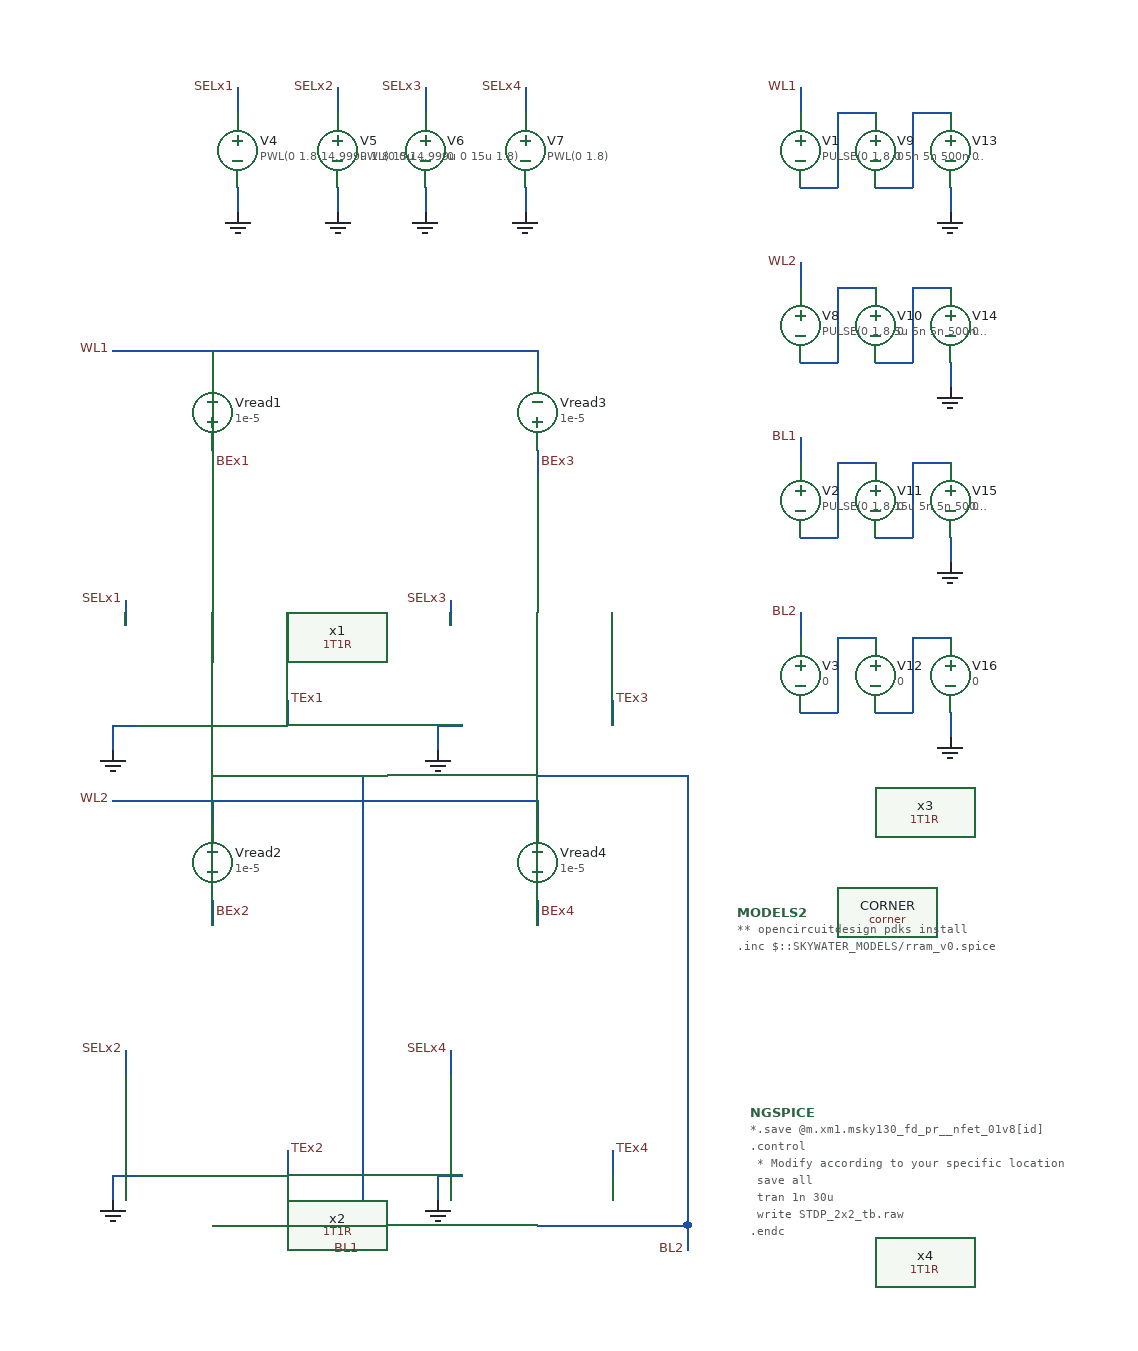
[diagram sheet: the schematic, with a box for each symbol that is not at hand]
v {xschem version=3.4.5 file_version=1.2
}
G {}
K {}
V {}
S {}
E {}
B 2 -930 -1240 -130 -840 {flags=graph
y1=-150000
y2=2.9e+06
ypos1=0
ypos2=2
divy=5
subdivy=1
unity=1
x1=0
x2=3e-05
divx=5
subdivx=1
xlabmag=1.0
ylabmag=1.0
node="\\"M[Ohms];\\"
\\"M1;TEx1 BEx1 - i(Vread1) /\\"
\\"M2;TEx2 BEx2 - i(Vread2) /\\"
\\"M3;TEx3 BEx3 - i(Vread3) /\\"
\\"M4;TEx4 BEx4 - i(Vread4) /\\""
color="4 8 6 7 10"
dataset=-1
unitx=1
logx=0
logy=0
}
B 2 -130 -1240 670 -840 {flags=graph
y1=0
y2=3
ypos1=0
ypos2=2
divy=5
subdivy=1
unity=1
x1=0
x2=3e-05
divx=5
subdivx=1
xlabmag=1.0
ylabmag=1.0
node="\\"SELx1[V];SELx1\\"
\\"SELx2[V];SELx2\\"
\\"SELx3[V];SELx3\\"
\\"SELx4[V];SELx4\\""
color="8 6 7 10"
dataset=-1
unitx=1
logx=0
logy=0
}
B 2 -930 -840 -130 -440 {flags=graph
y1=-5.3e-05
y2=6.6e-05
ypos1=0
ypos2=2
divy=5
subdivy=1
unity=1
x1=0
x2=3e-05
divx=5
subdivx=1
xlabmag=1.0
ylabmag=1.0


dataset=-1
unitx=1
logx=0
logy=0
color="4 8 6 7 10"
node="\\"Current (A);\\"
\\"i1;0 i(Vread1) -\\"
\\"i2;0 i(Vread2) -\\"
\\"i3;0 i(Vread3) -\\"
\\"i4;0 i(Vread4) -\\""}
B 2 -130 -840 670 -440 {flags=graph
y1=0
y2=1.8
ypos1=0
ypos2=2
divy=5
subdivy=1
unity=1
x1=0
x2=3e-05
divx=5
subdivx=1
xlabmag=1.0
ylabmag=1.0


dataset=-1
unitx=1
logx=0
logy=0
color="4 8 6 7 10"
node="\\"Voltage (V);\\"
\\"WL1;WL1\\"
\\"WL2;WL2\\"
\\"BL1;BL1\\"
\\"BL2;BL2\\""}
N -1640 -690 -1520 -690 {
lab=BL1}
N -1640 -330 -1520 -330 {
lab=BL1}
N -1380 -330 -1260 -330 {
lab=BL2}
N -1380 -690 -1260 -690 {
lab=BL2}
N -1460 -730 -1460 -710 {
lab=GND}
N -1460 -730 -1440 -730 {
lab=GND}
N -1720 -730 -1720 -710 {
lab=GND}
N -1720 -730 -1700 -730 {
lab=GND}
N -1720 -370 -1720 -350 {
lab=GND}
N -1720 -370 -1700 -370 {
lab=GND}
N -1460 -370 -1460 -350 {
lab=GND}
N -1460 -370 -1440 -370 {
lab=GND}
N -1710 -830 -1710 -810 {
lab=SELx1}
N -1450 -830 -1450 -810 {
lab=SELx3}
N -1450 -470 -1450 -450 {
lab=SELx4}
N -1710 -470 -1710 -450 {
lab=SELx2}
N -1580 -390 -1580 -370 {
lab=TEx2}
N -1580 -750 -1580 -730 {
lab=TEx1}
N -1320 -750 -1320 -730 {
lab=TEx3}
N -1320 -390 -1320 -370 {
lab=TEx4}
N -1170 -1240 -1170 -1220 {
lab=WL1}
N -1170 -960 -1170 -940 {
lab=BL1}
N -1170 -820 -1170 -800 {
lab=BL2}
N -1520 -330 -1520 -310 {
lab=BL1}
N -1260 -330 -1260 -310 {
lab=BL2}
N -1620 -1160 -1620 -1140 {
lab=GND}
N -1620 -1240 -1620 -1220 {
lab=SELx1}
N -1540 -1160 -1540 -1140 {
lab=GND}
N -1540 -1240 -1540 -1220 {
lab=SELx2}
N -1470 -1160 -1470 -1140 {
lab=GND}
N -1470 -1240 -1470 -1220 {
lab=SELx3}
N -1390 -1160 -1390 -1140 {
lab=GND}
N -1390 -1240 -1390 -1220 {
lab=SELx4}
N -1380 -950 -1380 -930 {
lab=BEx3}
N -1640 -950 -1640 -930 {
lab=BEx1}
N -1720 -1030 -1380 -1030 {
lab=WL1}
N -1380 -1030 -1380 -1010 {
lab=WL1}
N -1640 -1030 -1640 -1010 {
lab=WL1}
N -1640 -590 -1640 -570 {
lab=BEx2}
N -1380 -590 -1380 -570 {
lab=BEx4}
N -1380 -670 -1380 -650 {
lab=WL2}
N -1720 -670 -1380 -670 {
lab=WL2}
N -1640 -670 -1640 -650 {
lab=WL2}
N -1520 -690 -1520 -330 {
lab=BL1}
N -1260 -690 -1260 -330 {
lab=BL2}
N -1170 -1100 -1170 -1080 {
lab=WL2}
N -1050 -1160 -1050 -1140 {
lab=GND}
N -1050 -1020 -1050 -1000 {
lab=GND}
N -1050 -880 -1050 -860 {
lab=GND}
N -1050 -740 -1050 -720 {
lab=GND}
N -1170 -740 -1140 -740 {
lab=#net1}
N -1140 -800 -1140 -740 {
lab=#net1}
N -1140 -800 -1110 -800 {
lab=#net1}
N -1110 -740 -1080 -740 {
lab=#net2}
N -1080 -800 -1080 -740 {
lab=#net2}
N -1080 -800 -1050 -800 {
lab=#net2}
N -1170 -880 -1140 -880 {
lab=#net3}
N -1140 -940 -1140 -880 {
lab=#net3}
N -1140 -940 -1110 -940 {
lab=#net3}
N -1110 -880 -1080 -880 {
lab=#net4}
N -1080 -940 -1080 -880 {
lab=#net4}
N -1080 -940 -1050 -940 {
lab=#net4}
N -1170 -1020 -1140 -1020 {
lab=#net5}
N -1140 -1080 -1140 -1020 {
lab=#net5}
N -1140 -1080 -1110 -1080 {
lab=#net5}
N -1110 -1020 -1080 -1020 {
lab=#net6}
N -1080 -1080 -1080 -1020 {
lab=#net6}
N -1080 -1080 -1050 -1080 {
lab=#net6}
N -1170 -1160 -1140 -1160 {
lab=#net7}
N -1140 -1220 -1140 -1160 {
lab=#net7}
N -1140 -1220 -1110 -1220 {
lab=#net7}
N -1110 -1160 -1080 -1160 {
lab=#net8}
N -1080 -1220 -1080 -1160 {
lab=#net8}
N -1080 -1220 -1050 -1220 {
lab=#net8}
C {/home/ricardo/RATT_repos/Proyectos_xschem/1T1R/1T1R.sym} -1330 -660 0 0 {name=x1}
C {/home/ricardo/RATT_repos/Proyectos_xschem/1T1R/1T1R.sym} -1330 -300 0 0 {name=x2}
C {/home/ricardo/RATT_repos/Proyectos_xschem/1T1R/1T1R.sym} -1070 -660 0 0 {name=x3}
C {/home/ricardo/RATT_repos/Proyectos_xschem/1T1R/1T1R.sym} -1070 -300 0 0 {name=x4}
C {devices/gnd.sym} -1460 -710 0 0 {name=l1 lab=GND}
C {devices/gnd.sym} -1720 -710 0 0 {name=l2 lab=GND}
C {devices/gnd.sym} -1720 -350 0 0 {name=l3 lab=GND}
C {devices/gnd.sym} -1460 -350 0 0 {name=l4 lab=GND}
C {devices/lab_pin.sym} -1710 -830 0 0 {name=p1 sig_type=std_logic lab=SELx1}
C {devices/lab_pin.sym} -1450 -830 0 0 {name=p2 sig_type=std_logic lab=SELx3}
C {devices/lab_pin.sym} -1450 -470 0 0 {name=p3 sig_type=std_logic lab=SELx4}
C {devices/lab_pin.sym} -1710 -470 0 0 {name=p4 sig_type=std_logic lab=SELx2}
C {devices/lab_pin.sym} -1580 -390 2 0 {name=p5 sig_type=std_logic lab=TEx2}
C {devices/lab_pin.sym} -1580 -750 2 0 {name=p6 sig_type=std_logic lab=TEx1}
C {devices/lab_pin.sym} -1320 -750 2 0 {name=p7 sig_type=std_logic lab=TEx3}
C {devices/lab_pin.sym} -1320 -390 2 0 {name=p8 sig_type=std_logic lab=TEx4}
C {devices/vsource.sym} -1170 -1190 0 0 {name=V1 value="PULSE(0 1.8 0 5n 5n 500n 1000n 10)"}
C {devices/lab_pin.sym} -1170 -1240 0 0 {name=p9 sig_type=std_logic lab=WL1}
C {devices/vsource.sym} -1170 -910 0 0 {name=V2 value="PULSE(0 1.8 15u 5n 5n 500n 1000n 10)"}
C {devices/lab_pin.sym} -1170 -960 0 0 {name=p11 sig_type=std_logic lab=BL1}
C {devices/vsource.sym} -1170 -770 0 0 {name=V3 value=0}
C {devices/lab_pin.sym} -1170 -820 0 0 {name=p12 sig_type=std_logic lab=BL2}
C {devices/lab_pin.sym} -1520 -310 0 0 {name=p13 sig_type=std_logic lab=BL1}
C {devices/lab_pin.sym} -1260 -310 0 0 {name=p14 sig_type=std_logic lab=BL2}
C {devices/lab_pin.sym} -1720 -1030 0 0 {name=p15 sig_type=std_logic lab=WL1}
C {devices/lab_pin.sym} -1720 -670 0 0 {name=p16 sig_type=std_logic lab=WL2}
C {devices/vsource.sym} -1620 -1190 0 0 {name=V4
value="PWL(0 1.8 14.999u 1.8 15u 3)"}
C {devices/gnd.sym} -1620 -1140 0 0 {name=l8 lab=GND}
C {devices/lab_pin.sym} -1620 -1240 0 0 {name=p10 sig_type=std_logic lab=SELx1}
C {devices/vsource.sym} -1540 -1190 0 0 {name=V5
value="PWL(0 0 14.999u 0 15u 1.8)"}
C {devices/gnd.sym} -1540 -1140 0 0 {name=l9 lab=GND}
C {devices/lab_pin.sym} -1540 -1240 0 0 {name=p17 sig_type=std_logic lab=SELx2}
C {devices/vsource.sym} -1470 -1190 0 0 {name=V6
value=0}
C {devices/gnd.sym} -1470 -1140 0 0 {name=l10 lab=GND}
C {devices/lab_pin.sym} -1470 -1240 0 0 {name=p18 sig_type=std_logic lab=SELx3}
C {devices/vsource.sym} -1390 -1190 0 0 {name=V7
value="PWL(0 1.8)"}
C {devices/gnd.sym} -1390 -1140 0 0 {name=l11 lab=GND}
C {devices/lab_pin.sym} -1390 -1240 0 0 {name=p19 sig_type=std_logic lab=SELx4}
C {devices/code_shown.sym} -1210 -420 0 0 {name=NGSPICE
only_toplevel=true
value="
*.save @m.xm1.msky130_fd_pr__nfet_01v8[id]
.control
  * Modify according to your specific location
  save all
  tran 1n 30u
  write STDP_2x2_tb.raw
.endc

" }
C {sky130_fd_pr/corner.sym} -1100 -580 0 0 {name=CORNER only_toplevel=true corner=tt}
C {devices/launcher.sym} -1160 -660 0 0 {name=h5
descr="load waves" 
tclcommand="xschem raw_read $netlist_dir/STDP_2x2_tb.raw tran"
}
C {devices/code.sym} -1220 -580 0 0 {name=MODELS2
only_toplevel=true
format="tcleval( @value )"
value="
** opencircuitdesign pdks install
.inc $::SKYWATER_MODELS/rram_v0.spice
"
spice_ignore=false}
C {devices/vsource.sym} -1640 -980 2 0 {name=Vread1 value=1e-5}
C {devices/vsource.sym} -1380 -980 2 0 {name=Vread3 value=1e-5}
C {devices/vsource.sym} -1640 -620 2 0 {name=Vread2 value=1e-5}
C {devices/vsource.sym} -1380 -620 2 0 {name=Vread4 value=1e-5}
C {devices/lab_pin.sym} -1640 -940 2 0 {name=p20 sig_type=std_logic lab=BEx1}
C {devices/lab_pin.sym} -1640 -580 2 0 {name=p21 sig_type=std_logic lab=BEx2}
C {devices/lab_pin.sym} -1380 -580 2 0 {name=p22 sig_type=std_logic lab=BEx4}
C {devices/lab_pin.sym} -1380 -940 2 0 {name=p23 sig_type=std_logic lab=BEx3}
C {devices/vsource.sym} -1170 -1050 0 0 {name=V8 value="PULSE(0 1.8 5u 5n 5n 500n 1000n 10)"}
C {devices/lab_pin.sym} -1170 -1100 0 0 {name=p24 sig_type=std_logic lab=WL2}
C {devices/vsource.sym} -1110 -1190 0 0 {name=V9 value=0}
C {devices/vsource.sym} -1110 -1050 0 0 {name=V10 value=0}
C {devices/vsource.sym} -1110 -910 0 0 {name=V11 value=0}
C {devices/vsource.sym} -1110 -770 0 0 {name=V12 value=0}
C {devices/vsource.sym} -1050 -1190 0 0 {name=V13 value=0}
C {devices/gnd.sym} -1050 -1140 0 0 {name=l17 lab=GND}
C {devices/vsource.sym} -1050 -1050 0 0 {name=V14 value=0}
C {devices/gnd.sym} -1050 -1000 0 0 {name=l18 lab=GND}
C {devices/vsource.sym} -1050 -910 0 0 {name=V15 value=0}
C {devices/gnd.sym} -1050 -860 0 0 {name=l19 lab=GND}
C {devices/vsource.sym} -1050 -770 0 0 {name=V16 value=0}
C {devices/gnd.sym} -1050 -720 0 0 {name=l20 lab=GND}
